VERSION 5.7 ;
  NOWIREEXTENSIONATPIN ON ;
  DIVIDERCHAR "/" ;
  BUSBITCHARS "[]" ;
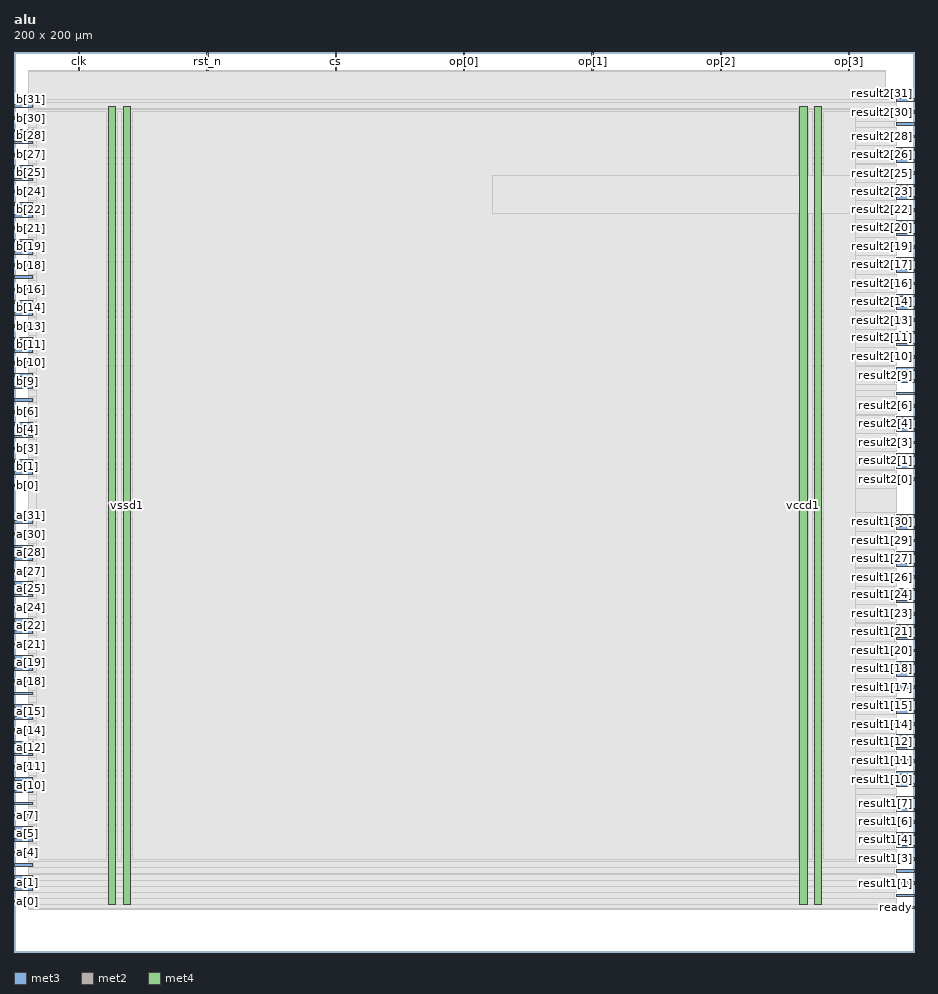
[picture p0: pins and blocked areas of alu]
MACRO alu
  CLASS BLOCK ;
  FOREIGN alu ;
  ORIGIN 0.000 0.000 ;
  SIZE 200.000 BY 200.000 ;
  PIN a[0]
    DIRECTION INPUT ;
    USE SIGNAL ;
    ANTENNAGATEAREA 0.593700 ;
    ANTENNADIFFAREA 0.434700 ;
    PORT
      LAYER met3 ;
        RECT 0.000 10.920 4.000 11.520 ;
    END
  END a[0]
  PIN a[10]
    DIRECTION INPUT ;
    USE SIGNAL ;
    ANTENNAGATEAREA 0.593700 ;
    ANTENNADIFFAREA 0.434700 ;
    PORT
      LAYER met3 ;
        RECT 0.000 38.120 4.000 38.720 ;
    END
  END a[10]
  PIN a[11]
    DIRECTION INPUT ;
    USE SIGNAL ;
    ANTENNAGATEAREA 0.647700 ;
    ANTENNADIFFAREA 0.434700 ;
    PORT
      LAYER met3 ;
        RECT 0.000 40.840 4.000 41.440 ;
    END
  END a[11]
  PIN a[12]
    DIRECTION INPUT ;
    USE SIGNAL ;
    ANTENNAGATEAREA 0.593700 ;
    ANTENNADIFFAREA 0.434700 ;
    PORT
      LAYER met3 ;
        RECT 0.000 43.560 4.000 44.160 ;
    END
  END a[12]
  PIN a[13]
    DIRECTION INPUT ;
    USE SIGNAL ;
    ANTENNAGATEAREA 0.593700 ;
    ANTENNADIFFAREA 0.434700 ;
    PORT
      LAYER met3 ;
        RECT 0.000 46.280 4.000 46.880 ;
    END
  END a[13]
  PIN a[14]
    DIRECTION INPUT ;
    USE SIGNAL ;
    ANTENNAGATEAREA 0.593700 ;
    ANTENNADIFFAREA 0.434700 ;
    PORT
      LAYER met3 ;
        RECT 0.000 49.000 4.000 49.600 ;
    END
  END a[14]
  PIN a[15]
    DIRECTION INPUT ;
    USE SIGNAL ;
    ANTENNAGATEAREA 0.593700 ;
    ANTENNADIFFAREA 0.434700 ;
    PORT
      LAYER met3 ;
        RECT 0.000 51.720 4.000 52.320 ;
    END
  END a[15]
  PIN a[16]
    DIRECTION INPUT ;
    USE SIGNAL ;
    ANTENNAGATEAREA 0.593700 ;
    ANTENNADIFFAREA 0.434700 ;
    PORT
      LAYER met3 ;
        RECT 0.000 54.440 4.000 55.040 ;
    END
  END a[16]
  PIN a[17]
    DIRECTION INPUT ;
    USE SIGNAL ;
    ANTENNAGATEAREA 0.647700 ;
    ANTENNADIFFAREA 0.434700 ;
    PORT
      LAYER met3 ;
        RECT 0.000 57.160 4.000 57.760 ;
    END
  END a[17]
  PIN a[18]
    DIRECTION INPUT ;
    USE SIGNAL ;
    ANTENNAGATEAREA 0.593700 ;
    ANTENNADIFFAREA 0.434700 ;
    PORT
      LAYER met3 ;
        RECT 0.000 59.880 4.000 60.480 ;
    END
  END a[18]
  PIN a[19]
    DIRECTION INPUT ;
    USE SIGNAL ;
    ANTENNAGATEAREA 0.593700 ;
    ANTENNADIFFAREA 0.434700 ;
    PORT
      LAYER met3 ;
        RECT 0.000 62.600 4.000 63.200 ;
    END
  END a[19]
  PIN a[1]
    DIRECTION INPUT ;
    USE SIGNAL ;
    ANTENNAGATEAREA 0.647700 ;
    ANTENNADIFFAREA 0.434700 ;
    PORT
      LAYER met3 ;
        RECT 0.000 13.640 4.000 14.240 ;
    END
  END a[1]
  PIN a[20]
    DIRECTION INPUT ;
    USE SIGNAL ;
    ANTENNAGATEAREA 0.647700 ;
    ANTENNADIFFAREA 0.434700 ;
    PORT
      LAYER met3 ;
        RECT 0.000 65.320 4.000 65.920 ;
    END
  END a[20]
  PIN a[21]
    DIRECTION INPUT ;
    USE SIGNAL ;
    ANTENNAGATEAREA 0.593700 ;
    ANTENNADIFFAREA 0.434700 ;
    PORT
      LAYER met3 ;
        RECT 0.000 68.040 4.000 68.640 ;
    END
  END a[21]
  PIN a[22]
    DIRECTION INPUT ;
    USE SIGNAL ;
    ANTENNAGATEAREA 0.593700 ;
    ANTENNADIFFAREA 0.434700 ;
    PORT
      LAYER met3 ;
        RECT 0.000 70.760 4.000 71.360 ;
    END
  END a[22]
  PIN a[23]
    DIRECTION INPUT ;
    USE SIGNAL ;
    ANTENNAGATEAREA 0.593700 ;
    ANTENNADIFFAREA 0.434700 ;
    PORT
      LAYER met3 ;
        RECT 0.000 73.480 4.000 74.080 ;
    END
  END a[23]
  PIN a[24]
    DIRECTION INPUT ;
    USE SIGNAL ;
    ANTENNAGATEAREA 0.593700 ;
    ANTENNADIFFAREA 0.434700 ;
    PORT
      LAYER met3 ;
        RECT 0.000 76.200 4.000 76.800 ;
    END
  END a[24]
  PIN a[25]
    DIRECTION INPUT ;
    USE SIGNAL ;
    ANTENNAGATEAREA 0.593700 ;
    ANTENNADIFFAREA 0.434700 ;
    PORT
      LAYER met3 ;
        RECT 0.000 78.920 4.000 79.520 ;
    END
  END a[25]
  PIN a[26]
    DIRECTION INPUT ;
    USE SIGNAL ;
    ANTENNAGATEAREA 0.593700 ;
    ANTENNADIFFAREA 0.434700 ;
    PORT
      LAYER met3 ;
        RECT 0.000 81.640 4.000 82.240 ;
    END
  END a[26]
  PIN a[27]
    DIRECTION INPUT ;
    USE SIGNAL ;
    ANTENNAGATEAREA 0.647700 ;
    ANTENNADIFFAREA 0.434700 ;
    PORT
      LAYER met3 ;
        RECT 0.000 84.360 4.000 84.960 ;
    END
  END a[27]
  PIN a[28]
    DIRECTION INPUT ;
    USE SIGNAL ;
    ANTENNAGATEAREA 0.593700 ;
    ANTENNADIFFAREA 0.434700 ;
    PORT
      LAYER met3 ;
        RECT 0.000 87.080 4.000 87.680 ;
    END
  END a[28]
  PIN a[29]
    DIRECTION INPUT ;
    USE SIGNAL ;
    ANTENNAGATEAREA 0.647700 ;
    ANTENNADIFFAREA 0.434700 ;
    PORT
      LAYER met3 ;
        RECT 0.000 89.800 4.000 90.400 ;
    END
  END a[29]
  PIN a[2]
    DIRECTION INPUT ;
    USE SIGNAL ;
    ANTENNAGATEAREA 0.647700 ;
    ANTENNADIFFAREA 0.434700 ;
    PORT
      LAYER met3 ;
        RECT 0.000 16.360 4.000 16.960 ;
    END
  END a[2]
  PIN a[30]
    DIRECTION INPUT ;
    USE SIGNAL ;
    ANTENNAGATEAREA 0.593700 ;
    ANTENNADIFFAREA 0.434700 ;
    PORT
      LAYER met3 ;
        RECT 0.000 92.520 4.000 93.120 ;
    END
  END a[30]
  PIN a[31]
    DIRECTION INPUT ;
    USE SIGNAL ;
    ANTENNAGATEAREA 0.647700 ;
    ANTENNADIFFAREA 0.434700 ;
    PORT
      LAYER met3 ;
        RECT 0.000 95.240 4.000 95.840 ;
    END
  END a[31]
  PIN a[3]
    DIRECTION INPUT ;
    USE SIGNAL ;
    ANTENNAGATEAREA 0.647700 ;
    ANTENNADIFFAREA 0.434700 ;
    PORT
      LAYER met3 ;
        RECT 0.000 19.080 4.000 19.680 ;
    END
  END a[3]
  PIN a[4]
    DIRECTION INPUT ;
    USE SIGNAL ;
    ANTENNAGATEAREA 0.647700 ;
    ANTENNADIFFAREA 0.434700 ;
    PORT
      LAYER met3 ;
        RECT 0.000 21.800 4.000 22.400 ;
    END
  END a[4]
  PIN a[5]
    DIRECTION INPUT ;
    USE SIGNAL ;
    ANTENNAGATEAREA 0.647700 ;
    ANTENNADIFFAREA 0.434700 ;
    PORT
      LAYER met3 ;
        RECT 0.000 24.520 4.000 25.120 ;
    END
  END a[5]
  PIN a[6]
    DIRECTION INPUT ;
    USE SIGNAL ;
    ANTENNAGATEAREA 0.647700 ;
    ANTENNADIFFAREA 0.434700 ;
    PORT
      LAYER met3 ;
        RECT 0.000 27.240 4.000 27.840 ;
    END
  END a[6]
  PIN a[7]
    DIRECTION INPUT ;
    USE SIGNAL ;
    ANTENNAGATEAREA 0.647700 ;
    ANTENNADIFFAREA 0.434700 ;
    PORT
      LAYER met3 ;
        RECT 0.000 29.960 4.000 30.560 ;
    END
  END a[7]
  PIN a[8]
    DIRECTION INPUT ;
    USE SIGNAL ;
    ANTENNAGATEAREA 0.647700 ;
    ANTENNADIFFAREA 0.434700 ;
    PORT
      LAYER met3 ;
        RECT 0.000 32.680 4.000 33.280 ;
    END
  END a[8]
  PIN a[9]
    DIRECTION INPUT ;
    USE SIGNAL ;
    ANTENNAGATEAREA 0.647700 ;
    ANTENNADIFFAREA 0.434700 ;
    PORT
      LAYER met3 ;
        RECT 0.000 35.400 4.000 36.000 ;
    END
  END a[9]
  PIN b[0]
    DIRECTION INPUT ;
    USE SIGNAL ;
    ANTENNAGATEAREA 0.647700 ;
    ANTENNADIFFAREA 0.434700 ;
    PORT
      LAYER met3 ;
        RECT 0.000 103.400 4.000 104.000 ;
    END
  END b[0]
  PIN b[10]
    DIRECTION INPUT ;
    USE SIGNAL ;
    ANTENNAGATEAREA 0.593700 ;
    ANTENNADIFFAREA 0.434700 ;
    PORT
      LAYER met3 ;
        RECT 0.000 130.600 4.000 131.200 ;
    END
  END b[10]
  PIN b[11]
    DIRECTION INPUT ;
    USE SIGNAL ;
    ANTENNAGATEAREA 0.593700 ;
    ANTENNADIFFAREA 0.434700 ;
    PORT
      LAYER met3 ;
        RECT 0.000 133.320 4.000 133.920 ;
    END
  END b[11]
  PIN b[12]
    DIRECTION INPUT ;
    USE SIGNAL ;
    ANTENNAGATEAREA 0.593700 ;
    ANTENNADIFFAREA 0.434700 ;
    PORT
      LAYER met3 ;
        RECT 0.000 136.040 4.000 136.640 ;
    END
  END b[12]
  PIN b[13]
    DIRECTION INPUT ;
    USE SIGNAL ;
    ANTENNAGATEAREA 0.593700 ;
    ANTENNADIFFAREA 0.434700 ;
    PORT
      LAYER met3 ;
        RECT 0.000 138.760 4.000 139.360 ;
    END
  END b[13]
  PIN b[14]
    DIRECTION INPUT ;
    USE SIGNAL ;
    ANTENNAGATEAREA 0.593700 ;
    ANTENNADIFFAREA 0.434700 ;
    PORT
      LAYER met3 ;
        RECT 0.000 141.480 4.000 142.080 ;
    END
  END b[14]
  PIN b[15]
    DIRECTION INPUT ;
    USE SIGNAL ;
    ANTENNAGATEAREA 0.647700 ;
    ANTENNADIFFAREA 0.434700 ;
    PORT
      LAYER met3 ;
        RECT 0.000 144.200 4.000 144.800 ;
    END
  END b[15]
  PIN b[16]
    DIRECTION INPUT ;
    USE SIGNAL ;
    ANTENNAGATEAREA 0.593700 ;
    ANTENNADIFFAREA 0.434700 ;
    PORT
      LAYER met3 ;
        RECT 0.000 146.920 4.000 147.520 ;
    END
  END b[16]
  PIN b[17]
    DIRECTION INPUT ;
    USE SIGNAL ;
    ANTENNAGATEAREA 0.593700 ;
    ANTENNADIFFAREA 0.434700 ;
    PORT
      LAYER met3 ;
        RECT 0.000 149.640 4.000 150.240 ;
    END
  END b[17]
  PIN b[18]
    DIRECTION INPUT ;
    USE SIGNAL ;
    ANTENNAGATEAREA 0.593700 ;
    ANTENNADIFFAREA 0.434700 ;
    PORT
      LAYER met3 ;
        RECT 0.000 152.360 4.000 152.960 ;
    END
  END b[18]
  PIN b[19]
    DIRECTION INPUT ;
    USE SIGNAL ;
    ANTENNAGATEAREA 0.593700 ;
    ANTENNADIFFAREA 0.434700 ;
    PORT
      LAYER met3 ;
        RECT 0.000 155.080 4.000 155.680 ;
    END
  END b[19]
  PIN b[1]
    DIRECTION INPUT ;
    USE SIGNAL ;
    ANTENNAGATEAREA 0.631200 ;
    ANTENNADIFFAREA 0.434700 ;
    PORT
      LAYER met3 ;
        RECT 0.000 106.120 4.000 106.720 ;
    END
  END b[1]
  PIN b[20]
    DIRECTION INPUT ;
    USE SIGNAL ;
    ANTENNAGATEAREA 0.647700 ;
    ANTENNADIFFAREA 0.434700 ;
    PORT
      LAYER met3 ;
        RECT 0.000 157.800 4.000 158.400 ;
    END
  END b[20]
  PIN b[21]
    DIRECTION INPUT ;
    USE SIGNAL ;
    ANTENNAGATEAREA 0.647700 ;
    ANTENNADIFFAREA 0.434700 ;
    PORT
      LAYER met3 ;
        RECT 0.000 160.520 4.000 161.120 ;
    END
  END b[21]
  PIN b[22]
    DIRECTION INPUT ;
    USE SIGNAL ;
    ANTENNAGATEAREA 0.593700 ;
    ANTENNADIFFAREA 0.434700 ;
    PORT
      LAYER met3 ;
        RECT 0.000 163.240 4.000 163.840 ;
    END
  END b[22]
  PIN b[23]
    DIRECTION INPUT ;
    USE SIGNAL ;
    ANTENNAGATEAREA 0.593700 ;
    ANTENNADIFFAREA 0.434700 ;
    PORT
      LAYER met3 ;
        RECT 0.000 165.960 4.000 166.560 ;
    END
  END b[23]
  PIN b[24]
    DIRECTION INPUT ;
    USE SIGNAL ;
    ANTENNAGATEAREA 0.593700 ;
    ANTENNADIFFAREA 0.434700 ;
    PORT
      LAYER met3 ;
        RECT 0.000 168.680 4.000 169.280 ;
    END
  END b[24]
  PIN b[25]
    DIRECTION INPUT ;
    USE SIGNAL ;
    ANTENNAGATEAREA 0.593700 ;
    ANTENNADIFFAREA 0.434700 ;
    PORT
      LAYER met3 ;
        RECT 0.000 171.400 4.000 172.000 ;
    END
  END b[25]
  PIN b[26]
    DIRECTION INPUT ;
    USE SIGNAL ;
    ANTENNAGATEAREA 0.593700 ;
    ANTENNADIFFAREA 0.434700 ;
    PORT
      LAYER met3 ;
        RECT 0.000 174.120 4.000 174.720 ;
    END
  END b[26]
  PIN b[27]
    DIRECTION INPUT ;
    USE SIGNAL ;
    ANTENNAGATEAREA 0.647700 ;
    ANTENNADIFFAREA 0.434700 ;
    PORT
      LAYER met3 ;
        RECT 0.000 176.840 4.000 177.440 ;
    END
  END b[27]
  PIN b[28]
    DIRECTION INPUT ;
    USE SIGNAL ;
    ANTENNAGATEAREA 0.647700 ;
    ANTENNADIFFAREA 0.434700 ;
    PORT
      LAYER met3 ;
        RECT 0.000 179.560 4.000 180.160 ;
    END
  END b[28]
  PIN b[29]
    DIRECTION INPUT ;
    USE SIGNAL ;
    ANTENNAGATEAREA 0.647700 ;
    ANTENNADIFFAREA 0.434700 ;
    PORT
      LAYER met3 ;
        RECT 0.000 182.280 4.000 182.880 ;
    END
  END b[29]
  PIN b[2]
    DIRECTION INPUT ;
    USE SIGNAL ;
    ANTENNAGATEAREA 0.631200 ;
    ANTENNADIFFAREA 0.434700 ;
    PORT
      LAYER met3 ;
        RECT 0.000 108.840 4.000 109.440 ;
    END
  END b[2]
  PIN b[30]
    DIRECTION INPUT ;
    USE SIGNAL ;
    ANTENNAGATEAREA 0.647700 ;
    ANTENNADIFFAREA 0.434700 ;
    PORT
      LAYER met3 ;
        RECT 0.000 185.000 4.000 185.600 ;
    END
  END b[30]
  PIN b[31]
    DIRECTION INPUT ;
    USE SIGNAL ;
    ANTENNAGATEAREA 0.593700 ;
    ANTENNADIFFAREA 0.434700 ;
    PORT
      LAYER met3 ;
        RECT 0.000 187.720 4.000 188.320 ;
    END
  END b[31]
  PIN b[3]
    DIRECTION INPUT ;
    USE SIGNAL ;
    ANTENNAGATEAREA 0.631200 ;
    ANTENNADIFFAREA 0.434700 ;
    PORT
      LAYER met3 ;
        RECT 0.000 111.560 4.000 112.160 ;
    END
  END b[3]
  PIN b[4]
    DIRECTION INPUT ;
    USE SIGNAL ;
    ANTENNAGATEAREA 0.647700 ;
    ANTENNADIFFAREA 0.434700 ;
    PORT
      LAYER met3 ;
        RECT 0.000 114.280 4.000 114.880 ;
    END
  END b[4]
  PIN b[5]
    DIRECTION INPUT ;
    USE SIGNAL ;
    ANTENNAGATEAREA 0.647700 ;
    ANTENNADIFFAREA 0.434700 ;
    PORT
      LAYER met3 ;
        RECT 0.000 117.000 4.000 117.600 ;
    END
  END b[5]
  PIN b[6]
    DIRECTION INPUT ;
    USE SIGNAL ;
    ANTENNAGATEAREA 0.593700 ;
    ANTENNADIFFAREA 0.434700 ;
    PORT
      LAYER met3 ;
        RECT 0.000 119.720 4.000 120.320 ;
    END
  END b[6]
  PIN b[7]
    DIRECTION INPUT ;
    USE SIGNAL ;
    ANTENNAGATEAREA 0.593700 ;
    ANTENNADIFFAREA 0.434700 ;
    PORT
      LAYER met3 ;
        RECT 0.000 122.440 4.000 123.040 ;
    END
  END b[7]
  PIN b[8]
    DIRECTION INPUT ;
    USE SIGNAL ;
    ANTENNAGATEAREA 0.647700 ;
    ANTENNADIFFAREA 0.434700 ;
    PORT
      LAYER met3 ;
        RECT 0.000 125.160 4.000 125.760 ;
    END
  END b[8]
  PIN b[9]
    DIRECTION INPUT ;
    USE SIGNAL ;
    ANTENNAGATEAREA 0.647700 ;
    ANTENNADIFFAREA 0.434700 ;
    PORT
      LAYER met3 ;
        RECT 0.000 127.880 4.000 128.480 ;
    END
  END b[9]
  PIN clk
    DIRECTION INPUT ;
    USE SIGNAL ;
    ANTENNAGATEAREA 1.286700 ;
    ANTENNADIFFAREA 0.434700 ;
    PORT
      LAYER met2 ;
        RECT 14.350 196.000 14.630 200.000 ;
    END
  END clk
  PIN cs
    DIRECTION INPUT ;
    USE SIGNAL ;
    ANTENNAGATEAREA 0.647700 ;
    ANTENNADIFFAREA 0.434700 ;
    PORT
      LAYER met2 ;
        RECT 71.390 196.000 71.670 200.000 ;
    END
  END cs
  PIN op[0]
    DIRECTION INPUT ;
    USE SIGNAL ;
    ANTENNAGATEAREA 0.560700 ;
    ANTENNADIFFAREA 0.434700 ;
    PORT
      LAYER met2 ;
        RECT 99.910 196.000 100.190 200.000 ;
    END
  END op[0]
  PIN op[1]
    DIRECTION INPUT ;
    USE SIGNAL ;
    ANTENNAGATEAREA 0.647700 ;
    ANTENNADIFFAREA 0.434700 ;
    PORT
      LAYER met2 ;
        RECT 128.430 196.000 128.710 200.000 ;
    END
  END op[1]
  PIN op[2]
    DIRECTION INPUT ;
    USE SIGNAL ;
    ANTENNAGATEAREA 0.647700 ;
    ANTENNADIFFAREA 0.434700 ;
    PORT
      LAYER met2 ;
        RECT 156.950 196.000 157.230 200.000 ;
    END
  END op[2]
  PIN op[3]
    DIRECTION INPUT ;
    USE SIGNAL ;
    ANTENNAGATEAREA 0.593700 ;
    ANTENNADIFFAREA 0.434700 ;
    PORT
      LAYER met2 ;
        RECT 185.470 196.000 185.750 200.000 ;
    END
  END op[3]
  PIN ready
    DIRECTION OUTPUT ;
    USE SIGNAL ;
    ANTENNADIFFAREA 0.445500 ;
    PORT
      LAYER met3 ;
        RECT 196.000 9.560 200.000 10.160 ;
    END
  END ready
  PIN result1[0]
    DIRECTION OUTPUT ;
    USE SIGNAL ;
    ANTENNADIFFAREA 0.445500 ;
    PORT
      LAYER met3 ;
        RECT 196.000 12.280 200.000 12.880 ;
    END
  END result1[0]
  PIN result1[10]
    DIRECTION OUTPUT ;
    USE SIGNAL ;
    ANTENNADIFFAREA 0.445500 ;
    PORT
      LAYER met3 ;
        RECT 196.000 39.480 200.000 40.080 ;
    END
  END result1[10]
  PIN result1[11]
    DIRECTION OUTPUT ;
    USE SIGNAL ;
    ANTENNADIFFAREA 0.445500 ;
    PORT
      LAYER met3 ;
        RECT 196.000 42.200 200.000 42.800 ;
    END
  END result1[11]
  PIN result1[12]
    DIRECTION OUTPUT ;
    USE SIGNAL ;
    ANTENNADIFFAREA 0.445500 ;
    PORT
      LAYER met3 ;
        RECT 196.000 44.920 200.000 45.520 ;
    END
  END result1[12]
  PIN result1[13]
    DIRECTION OUTPUT ;
    USE SIGNAL ;
    ANTENNADIFFAREA 0.445500 ;
    PORT
      LAYER met3 ;
        RECT 196.000 47.640 200.000 48.240 ;
    END
  END result1[13]
  PIN result1[14]
    DIRECTION OUTPUT ;
    USE SIGNAL ;
    ANTENNADIFFAREA 0.445500 ;
    PORT
      LAYER met3 ;
        RECT 196.000 50.360 200.000 50.960 ;
    END
  END result1[14]
  PIN result1[15]
    DIRECTION OUTPUT ;
    USE SIGNAL ;
    ANTENNADIFFAREA 0.445500 ;
    PORT
      LAYER met3 ;
        RECT 196.000 53.080 200.000 53.680 ;
    END
  END result1[15]
  PIN result1[16]
    DIRECTION OUTPUT ;
    USE SIGNAL ;
    ANTENNADIFFAREA 0.445500 ;
    PORT
      LAYER met3 ;
        RECT 196.000 55.800 200.000 56.400 ;
    END
  END result1[16]
  PIN result1[17]
    DIRECTION OUTPUT ;
    USE SIGNAL ;
    ANTENNADIFFAREA 0.445500 ;
    PORT
      LAYER met3 ;
        RECT 196.000 58.520 200.000 59.120 ;
    END
  END result1[17]
  PIN result1[18]
    DIRECTION OUTPUT ;
    USE SIGNAL ;
    ANTENNADIFFAREA 0.445500 ;
    PORT
      LAYER met3 ;
        RECT 196.000 61.240 200.000 61.840 ;
    END
  END result1[18]
  PIN result1[19]
    DIRECTION OUTPUT ;
    USE SIGNAL ;
    ANTENNADIFFAREA 0.445500 ;
    PORT
      LAYER met3 ;
        RECT 196.000 63.960 200.000 64.560 ;
    END
  END result1[19]
  PIN result1[1]
    DIRECTION OUTPUT ;
    USE SIGNAL ;
    ANTENNADIFFAREA 0.445500 ;
    PORT
      LAYER met3 ;
        RECT 196.000 15.000 200.000 15.600 ;
    END
  END result1[1]
  PIN result1[20]
    DIRECTION OUTPUT ;
    USE SIGNAL ;
    ANTENNADIFFAREA 0.445500 ;
    PORT
      LAYER met3 ;
        RECT 196.000 66.680 200.000 67.280 ;
    END
  END result1[20]
  PIN result1[21]
    DIRECTION OUTPUT ;
    USE SIGNAL ;
    ANTENNADIFFAREA 0.445500 ;
    PORT
      LAYER met3 ;
        RECT 196.000 69.400 200.000 70.000 ;
    END
  END result1[21]
  PIN result1[22]
    DIRECTION OUTPUT ;
    USE SIGNAL ;
    ANTENNADIFFAREA 0.445500 ;
    PORT
      LAYER met3 ;
        RECT 196.000 72.120 200.000 72.720 ;
    END
  END result1[22]
  PIN result1[23]
    DIRECTION OUTPUT ;
    USE SIGNAL ;
    ANTENNADIFFAREA 0.445500 ;
    PORT
      LAYER met3 ;
        RECT 196.000 74.840 200.000 75.440 ;
    END
  END result1[23]
  PIN result1[24]
    DIRECTION OUTPUT ;
    USE SIGNAL ;
    ANTENNADIFFAREA 0.445500 ;
    PORT
      LAYER met3 ;
        RECT 196.000 77.560 200.000 78.160 ;
    END
  END result1[24]
  PIN result1[25]
    DIRECTION OUTPUT ;
    USE SIGNAL ;
    ANTENNADIFFAREA 0.445500 ;
    PORT
      LAYER met3 ;
        RECT 196.000 80.280 200.000 80.880 ;
    END
  END result1[25]
  PIN result1[26]
    DIRECTION OUTPUT ;
    USE SIGNAL ;
    ANTENNADIFFAREA 0.445500 ;
    PORT
      LAYER met3 ;
        RECT 196.000 83.000 200.000 83.600 ;
    END
  END result1[26]
  PIN result1[27]
    DIRECTION OUTPUT ;
    USE SIGNAL ;
    ANTENNADIFFAREA 0.445500 ;
    PORT
      LAYER met3 ;
        RECT 196.000 85.720 200.000 86.320 ;
    END
  END result1[27]
  PIN result1[28]
    DIRECTION OUTPUT ;
    USE SIGNAL ;
    ANTENNADIFFAREA 0.445500 ;
    PORT
      LAYER met3 ;
        RECT 196.000 88.440 200.000 89.040 ;
    END
  END result1[28]
  PIN result1[29]
    DIRECTION OUTPUT ;
    USE SIGNAL ;
    ANTENNADIFFAREA 0.445500 ;
    PORT
      LAYER met3 ;
        RECT 196.000 91.160 200.000 91.760 ;
    END
  END result1[29]
  PIN result1[2]
    DIRECTION OUTPUT ;
    USE SIGNAL ;
    ANTENNADIFFAREA 0.445500 ;
    PORT
      LAYER met3 ;
        RECT 196.000 17.720 200.000 18.320 ;
    END
  END result1[2]
  PIN result1[30]
    DIRECTION OUTPUT ;
    USE SIGNAL ;
    ANTENNADIFFAREA 0.445500 ;
    PORT
      LAYER met3 ;
        RECT 196.000 93.880 200.000 94.480 ;
    END
  END result1[30]
  PIN result1[31]
    DIRECTION OUTPUT ;
    USE SIGNAL ;
    ANTENNADIFFAREA 0.445500 ;
    PORT
      LAYER met3 ;
        RECT 196.000 96.600 200.000 97.200 ;
    END
  END result1[31]
  PIN result1[3]
    DIRECTION OUTPUT ;
    USE SIGNAL ;
    ANTENNADIFFAREA 0.445500 ;
    PORT
      LAYER met3 ;
        RECT 196.000 20.440 200.000 21.040 ;
    END
  END result1[3]
  PIN result1[4]
    DIRECTION OUTPUT ;
    USE SIGNAL ;
    ANTENNADIFFAREA 0.445500 ;
    PORT
      LAYER met3 ;
        RECT 196.000 23.160 200.000 23.760 ;
    END
  END result1[4]
  PIN result1[5]
    DIRECTION OUTPUT ;
    USE SIGNAL ;
    ANTENNADIFFAREA 0.445500 ;
    PORT
      LAYER met3 ;
        RECT 196.000 25.880 200.000 26.480 ;
    END
  END result1[5]
  PIN result1[6]
    DIRECTION OUTPUT ;
    USE SIGNAL ;
    ANTENNADIFFAREA 0.445500 ;
    PORT
      LAYER met3 ;
        RECT 196.000 28.600 200.000 29.200 ;
    END
  END result1[6]
  PIN result1[7]
    DIRECTION OUTPUT ;
    USE SIGNAL ;
    ANTENNADIFFAREA 0.445500 ;
    PORT
      LAYER met3 ;
        RECT 196.000 31.320 200.000 31.920 ;
    END
  END result1[7]
  PIN result1[8]
    DIRECTION OUTPUT ;
    USE SIGNAL ;
    ANTENNADIFFAREA 0.445500 ;
    PORT
      LAYER met3 ;
        RECT 196.000 34.040 200.000 34.640 ;
    END
  END result1[8]
  PIN result1[9]
    DIRECTION OUTPUT ;
    USE SIGNAL ;
    ANTENNADIFFAREA 0.445500 ;
    PORT
      LAYER met3 ;
        RECT 196.000 36.760 200.000 37.360 ;
    END
  END result1[9]
  PIN result2[0]
    DIRECTION OUTPUT ;
    USE SIGNAL ;
    ANTENNADIFFAREA 0.445500 ;
    PORT
      LAYER met3 ;
        RECT 196.000 104.760 200.000 105.360 ;
    END
  END result2[0]
  PIN result2[10]
    DIRECTION OUTPUT ;
    USE SIGNAL ;
    ANTENNADIFFAREA 0.445500 ;
    PORT
      LAYER met3 ;
        RECT 196.000 131.960 200.000 132.560 ;
    END
  END result2[10]
  PIN result2[11]
    DIRECTION OUTPUT ;
    USE SIGNAL ;
    ANTENNADIFFAREA 0.445500 ;
    PORT
      LAYER met3 ;
        RECT 196.000 134.680 200.000 135.280 ;
    END
  END result2[11]
  PIN result2[12]
    DIRECTION OUTPUT ;
    USE SIGNAL ;
    ANTENNADIFFAREA 0.445500 ;
    PORT
      LAYER met3 ;
        RECT 196.000 137.400 200.000 138.000 ;
    END
  END result2[12]
  PIN result2[13]
    DIRECTION OUTPUT ;
    USE SIGNAL ;
    ANTENNADIFFAREA 0.445500 ;
    PORT
      LAYER met3 ;
        RECT 196.000 140.120 200.000 140.720 ;
    END
  END result2[13]
  PIN result2[14]
    DIRECTION OUTPUT ;
    USE SIGNAL ;
    ANTENNADIFFAREA 0.445500 ;
    PORT
      LAYER met3 ;
        RECT 196.000 142.840 200.000 143.440 ;
    END
  END result2[14]
  PIN result2[15]
    DIRECTION OUTPUT ;
    USE SIGNAL ;
    ANTENNADIFFAREA 0.445500 ;
    PORT
      LAYER met3 ;
        RECT 196.000 145.560 200.000 146.160 ;
    END
  END result2[15]
  PIN result2[16]
    DIRECTION OUTPUT ;
    USE SIGNAL ;
    ANTENNADIFFAREA 0.445500 ;
    PORT
      LAYER met3 ;
        RECT 196.000 148.280 200.000 148.880 ;
    END
  END result2[16]
  PIN result2[17]
    DIRECTION OUTPUT ;
    USE SIGNAL ;
    ANTENNADIFFAREA 0.445500 ;
    PORT
      LAYER met3 ;
        RECT 196.000 151.000 200.000 151.600 ;
    END
  END result2[17]
  PIN result2[18]
    DIRECTION OUTPUT ;
    USE SIGNAL ;
    ANTENNADIFFAREA 0.445500 ;
    PORT
      LAYER met3 ;
        RECT 196.000 153.720 200.000 154.320 ;
    END
  END result2[18]
  PIN result2[19]
    DIRECTION OUTPUT ;
    USE SIGNAL ;
    ANTENNADIFFAREA 0.445500 ;
    PORT
      LAYER met3 ;
        RECT 196.000 156.440 200.000 157.040 ;
    END
  END result2[19]
  PIN result2[1]
    DIRECTION OUTPUT ;
    USE SIGNAL ;
    ANTENNADIFFAREA 0.445500 ;
    PORT
      LAYER met3 ;
        RECT 196.000 107.480 200.000 108.080 ;
    END
  END result2[1]
  PIN result2[20]
    DIRECTION OUTPUT ;
    USE SIGNAL ;
    ANTENNADIFFAREA 0.445500 ;
    PORT
      LAYER met3 ;
        RECT 196.000 159.160 200.000 159.760 ;
    END
  END result2[20]
  PIN result2[21]
    DIRECTION OUTPUT ;
    USE SIGNAL ;
    ANTENNADIFFAREA 0.445500 ;
    PORT
      LAYER met3 ;
        RECT 196.000 161.880 200.000 162.480 ;
    END
  END result2[21]
  PIN result2[22]
    DIRECTION OUTPUT ;
    USE SIGNAL ;
    ANTENNADIFFAREA 0.445500 ;
    PORT
      LAYER met3 ;
        RECT 196.000 164.600 200.000 165.200 ;
    END
  END result2[22]
  PIN result2[23]
    DIRECTION OUTPUT ;
    USE SIGNAL ;
    ANTENNADIFFAREA 0.445500 ;
    PORT
      LAYER met3 ;
        RECT 196.000 167.320 200.000 167.920 ;
    END
  END result2[23]
  PIN result2[24]
    DIRECTION OUTPUT ;
    USE SIGNAL ;
    ANTENNADIFFAREA 0.445500 ;
    PORT
      LAYER met3 ;
        RECT 196.000 170.040 200.000 170.640 ;
    END
  END result2[24]
  PIN result2[25]
    DIRECTION OUTPUT ;
    USE SIGNAL ;
    ANTENNADIFFAREA 0.445500 ;
    PORT
      LAYER met3 ;
        RECT 196.000 172.760 200.000 173.360 ;
    END
  END result2[25]
  PIN result2[26]
    DIRECTION OUTPUT ;
    USE SIGNAL ;
    ANTENNADIFFAREA 0.445500 ;
    PORT
      LAYER met3 ;
        RECT 196.000 175.480 200.000 176.080 ;
    END
  END result2[26]
  PIN result2[27]
    DIRECTION OUTPUT ;
    USE SIGNAL ;
    ANTENNADIFFAREA 0.445500 ;
    PORT
      LAYER met3 ;
        RECT 196.000 178.200 200.000 178.800 ;
    END
  END result2[27]
  PIN result2[28]
    DIRECTION OUTPUT ;
    USE SIGNAL ;
    ANTENNADIFFAREA 0.445500 ;
    PORT
      LAYER met3 ;
        RECT 196.000 180.920 200.000 181.520 ;
    END
  END result2[28]
  PIN result2[29]
    DIRECTION OUTPUT ;
    USE SIGNAL ;
    ANTENNADIFFAREA 0.445500 ;
    PORT
      LAYER met3 ;
        RECT 196.000 183.640 200.000 184.240 ;
    END
  END result2[29]
  PIN result2[2]
    DIRECTION OUTPUT ;
    USE SIGNAL ;
    ANTENNADIFFAREA 0.445500 ;
    PORT
      LAYER met3 ;
        RECT 196.000 110.200 200.000 110.800 ;
    END
  END result2[2]
  PIN result2[30]
    DIRECTION OUTPUT ;
    USE SIGNAL ;
    ANTENNADIFFAREA 0.445500 ;
    PORT
      LAYER met3 ;
        RECT 196.000 186.360 200.000 186.960 ;
    END
  END result2[30]
  PIN result2[31]
    DIRECTION OUTPUT ;
    USE SIGNAL ;
    ANTENNADIFFAREA 0.445500 ;
    PORT
      LAYER met3 ;
        RECT 196.000 189.080 200.000 189.680 ;
    END
  END result2[31]
  PIN result2[3]
    DIRECTION OUTPUT ;
    USE SIGNAL ;
    ANTENNADIFFAREA 0.445500 ;
    PORT
      LAYER met3 ;
        RECT 196.000 112.920 200.000 113.520 ;
    END
  END result2[3]
  PIN result2[4]
    DIRECTION OUTPUT ;
    USE SIGNAL ;
    ANTENNADIFFAREA 0.445500 ;
    PORT
      LAYER met3 ;
        RECT 196.000 115.640 200.000 116.240 ;
    END
  END result2[4]
  PIN result2[5]
    DIRECTION OUTPUT ;
    USE SIGNAL ;
    ANTENNADIFFAREA 0.445500 ;
    PORT
      LAYER met3 ;
        RECT 196.000 118.360 200.000 118.960 ;
    END
  END result2[5]
  PIN result2[6]
    DIRECTION OUTPUT ;
    USE SIGNAL ;
    ANTENNADIFFAREA 0.445500 ;
    PORT
      LAYER met3 ;
        RECT 196.000 121.080 200.000 121.680 ;
    END
  END result2[6]
  PIN result2[7]
    DIRECTION OUTPUT ;
    USE SIGNAL ;
    ANTENNADIFFAREA 0.445500 ;
    PORT
      LAYER met3 ;
        RECT 196.000 123.800 200.000 124.400 ;
    END
  END result2[7]
  PIN result2[8]
    DIRECTION OUTPUT ;
    USE SIGNAL ;
    ANTENNADIFFAREA 0.445500 ;
    PORT
      LAYER met3 ;
        RECT 196.000 126.520 200.000 127.120 ;
    END
  END result2[8]
  PIN result2[9]
    DIRECTION OUTPUT ;
    USE SIGNAL ;
    ANTENNADIFFAREA 0.445500 ;
    PORT
      LAYER met3 ;
        RECT 196.000 129.240 200.000 129.840 ;
    END
  END result2[9]
  PIN rst_n
    DIRECTION INPUT ;
    USE SIGNAL ;
    ANTENNAGATEAREA 0.647700 ;
    ANTENNADIFFAREA 0.434700 ;
    PORT
      LAYER met2 ;
        RECT 42.870 196.000 43.150 200.000 ;
    END
  END rst_n
  PIN vccd1
    DIRECTION INOUT ;
    USE POWER ;
    PORT
      LAYER met4 ;
        RECT 21.040 10.640 22.640 187.920 ;
    END
    PORT
      LAYER met4 ;
        RECT 174.640 10.640 176.240 187.920 ;
    END
  END vccd1
  PIN vssd1
    DIRECTION INOUT ;
    USE GROUND ;
    PORT
      LAYER met4 ;
        RECT 24.340 10.640 25.940 187.920 ;
    END
    PORT
      LAYER met4 ;
        RECT 177.940 10.640 179.540 187.920 ;
    END
  END vssd1
  OBS
      LAYER nwell ;
        RECT 5.330 10.795 194.310 187.870 ;
      LAYER li1 ;
        RECT 5.520 10.795 194.120 187.765 ;
      LAYER met1 ;
        RECT 3.290 9.560 194.120 190.020 ;
      LAYER met2 ;
        RECT 3.310 195.720 14.070 196.000 ;
        RECT 14.910 195.720 42.590 196.000 ;
        RECT 43.430 195.720 71.110 196.000 ;
        RECT 71.950 195.720 99.630 196.000 ;
        RECT 100.470 195.720 128.150 196.000 ;
        RECT 128.990 195.720 156.670 196.000 ;
        RECT 157.510 195.720 185.190 196.000 ;
        RECT 186.030 195.720 193.570 196.000 ;
        RECT 3.310 9.530 193.570 195.720 ;
      LAYER met3 ;
        RECT 3.285 188.720 195.600 189.545 ;
        RECT 4.400 188.680 195.600 188.720 ;
        RECT 4.400 187.360 196.000 188.680 ;
        RECT 4.400 187.320 195.600 187.360 ;
        RECT 3.285 186.000 195.600 187.320 ;
        RECT 4.400 185.960 195.600 186.000 ;
        RECT 4.400 184.640 196.000 185.960 ;
        RECT 4.400 184.600 195.600 184.640 ;
        RECT 3.285 183.280 195.600 184.600 ;
        RECT 4.400 183.240 195.600 183.280 ;
        RECT 4.400 181.920 196.000 183.240 ;
        RECT 4.400 181.880 195.600 181.920 ;
        RECT 3.285 180.560 195.600 181.880 ;
        RECT 4.400 180.520 195.600 180.560 ;
        RECT 4.400 179.200 196.000 180.520 ;
        RECT 4.400 179.160 195.600 179.200 ;
        RECT 3.285 177.840 195.600 179.160 ;
        RECT 4.400 177.800 195.600 177.840 ;
        RECT 4.400 176.480 196.000 177.800 ;
        RECT 4.400 176.440 195.600 176.480 ;
        RECT 3.285 175.120 195.600 176.440 ;
        RECT 4.400 175.080 195.600 175.120 ;
        RECT 4.400 173.760 196.000 175.080 ;
        RECT 4.400 173.720 195.600 173.760 ;
        RECT 3.285 172.400 195.600 173.720 ;
        RECT 4.400 172.360 195.600 172.400 ;
        RECT 4.400 171.040 196.000 172.360 ;
        RECT 4.400 171.000 195.600 171.040 ;
        RECT 3.285 169.680 195.600 171.000 ;
        RECT 4.400 169.640 195.600 169.680 ;
        RECT 4.400 168.320 196.000 169.640 ;
        RECT 4.400 168.280 195.600 168.320 ;
        RECT 3.285 166.960 195.600 168.280 ;
        RECT 4.400 166.920 195.600 166.960 ;
        RECT 4.400 165.600 196.000 166.920 ;
        RECT 4.400 165.560 195.600 165.600 ;
        RECT 3.285 164.240 195.600 165.560 ;
        RECT 4.400 164.200 195.600 164.240 ;
        RECT 4.400 162.880 196.000 164.200 ;
        RECT 4.400 162.840 195.600 162.880 ;
        RECT 3.285 161.520 195.600 162.840 ;
        RECT 4.400 161.480 195.600 161.520 ;
        RECT 4.400 160.160 196.000 161.480 ;
        RECT 4.400 160.120 195.600 160.160 ;
        RECT 3.285 158.800 195.600 160.120 ;
        RECT 4.400 158.760 195.600 158.800 ;
        RECT 4.400 157.440 196.000 158.760 ;
        RECT 4.400 157.400 195.600 157.440 ;
        RECT 3.285 156.080 195.600 157.400 ;
        RECT 4.400 156.040 195.600 156.080 ;
        RECT 4.400 154.720 196.000 156.040 ;
        RECT 4.400 154.680 195.600 154.720 ;
        RECT 3.285 153.360 195.600 154.680 ;
        RECT 4.400 153.320 195.600 153.360 ;
        RECT 4.400 152.000 196.000 153.320 ;
        RECT 4.400 151.960 195.600 152.000 ;
        RECT 3.285 150.640 195.600 151.960 ;
        RECT 4.400 150.600 195.600 150.640 ;
        RECT 4.400 149.280 196.000 150.600 ;
        RECT 4.400 149.240 195.600 149.280 ;
        RECT 3.285 147.920 195.600 149.240 ;
        RECT 4.400 147.880 195.600 147.920 ;
        RECT 4.400 146.560 196.000 147.880 ;
        RECT 4.400 146.520 195.600 146.560 ;
        RECT 3.285 145.200 195.600 146.520 ;
        RECT 4.400 145.160 195.600 145.200 ;
        RECT 4.400 143.840 196.000 145.160 ;
        RECT 4.400 143.800 195.600 143.840 ;
        RECT 3.285 142.480 195.600 143.800 ;
        RECT 4.400 142.440 195.600 142.480 ;
        RECT 4.400 141.120 196.000 142.440 ;
        RECT 4.400 141.080 195.600 141.120 ;
        RECT 3.285 139.760 195.600 141.080 ;
        RECT 4.400 139.720 195.600 139.760 ;
        RECT 4.400 138.400 196.000 139.720 ;
        RECT 4.400 138.360 195.600 138.400 ;
        RECT 3.285 137.040 195.600 138.360 ;
        RECT 4.400 137.000 195.600 137.040 ;
        RECT 4.400 135.680 196.000 137.000 ;
        RECT 4.400 135.640 195.600 135.680 ;
        RECT 3.285 134.320 195.600 135.640 ;
        RECT 4.400 134.280 195.600 134.320 ;
        RECT 4.400 132.960 196.000 134.280 ;
        RECT 4.400 132.920 195.600 132.960 ;
        RECT 3.285 131.600 195.600 132.920 ;
        RECT 4.400 131.560 195.600 131.600 ;
        RECT 4.400 130.240 196.000 131.560 ;
        RECT 4.400 130.200 195.600 130.240 ;
        RECT 3.285 128.880 195.600 130.200 ;
        RECT 4.400 128.840 195.600 128.880 ;
        RECT 4.400 127.520 196.000 128.840 ;
        RECT 4.400 127.480 195.600 127.520 ;
        RECT 3.285 126.160 195.600 127.480 ;
        RECT 4.400 126.120 195.600 126.160 ;
        RECT 4.400 124.800 196.000 126.120 ;
        RECT 4.400 124.760 195.600 124.800 ;
        RECT 3.285 123.440 195.600 124.760 ;
        RECT 4.400 123.400 195.600 123.440 ;
        RECT 4.400 122.080 196.000 123.400 ;
        RECT 4.400 122.040 195.600 122.080 ;
        RECT 3.285 120.720 195.600 122.040 ;
        RECT 4.400 120.680 195.600 120.720 ;
        RECT 4.400 119.360 196.000 120.680 ;
        RECT 4.400 119.320 195.600 119.360 ;
        RECT 3.285 118.000 195.600 119.320 ;
        RECT 4.400 117.960 195.600 118.000 ;
        RECT 4.400 116.640 196.000 117.960 ;
        RECT 4.400 116.600 195.600 116.640 ;
        RECT 3.285 115.280 195.600 116.600 ;
        RECT 4.400 115.240 195.600 115.280 ;
        RECT 4.400 113.920 196.000 115.240 ;
        RECT 4.400 113.880 195.600 113.920 ;
        RECT 3.285 112.560 195.600 113.880 ;
        RECT 4.400 112.520 195.600 112.560 ;
        RECT 4.400 111.200 196.000 112.520 ;
        RECT 4.400 111.160 195.600 111.200 ;
        RECT 3.285 109.840 195.600 111.160 ;
        RECT 4.400 109.800 195.600 109.840 ;
        RECT 4.400 108.480 196.000 109.800 ;
        RECT 4.400 108.440 195.600 108.480 ;
        RECT 3.285 107.120 195.600 108.440 ;
        RECT 4.400 107.080 195.600 107.120 ;
        RECT 4.400 105.760 196.000 107.080 ;
        RECT 4.400 105.720 195.600 105.760 ;
        RECT 3.285 104.400 195.600 105.720 ;
        RECT 4.400 104.360 195.600 104.400 ;
        RECT 4.400 103.000 196.000 104.360 ;
        RECT 3.285 97.600 196.000 103.000 ;
        RECT 3.285 96.240 195.600 97.600 ;
        RECT 4.400 96.200 195.600 96.240 ;
        RECT 4.400 94.880 196.000 96.200 ;
        RECT 4.400 94.840 195.600 94.880 ;
        RECT 3.285 93.520 195.600 94.840 ;
        RECT 4.400 93.480 195.600 93.520 ;
        RECT 4.400 92.160 196.000 93.480 ;
        RECT 4.400 92.120 195.600 92.160 ;
        RECT 3.285 90.800 195.600 92.120 ;
        RECT 4.400 90.760 195.600 90.800 ;
        RECT 4.400 89.440 196.000 90.760 ;
        RECT 4.400 89.400 195.600 89.440 ;
        RECT 3.285 88.080 195.600 89.400 ;
        RECT 4.400 88.040 195.600 88.080 ;
        RECT 4.400 86.720 196.000 88.040 ;
        RECT 4.400 86.680 195.600 86.720 ;
        RECT 3.285 85.360 195.600 86.680 ;
        RECT 4.400 85.320 195.600 85.360 ;
        RECT 4.400 84.000 196.000 85.320 ;
        RECT 4.400 83.960 195.600 84.000 ;
        RECT 3.285 82.640 195.600 83.960 ;
        RECT 4.400 82.600 195.600 82.640 ;
        RECT 4.400 81.280 196.000 82.600 ;
        RECT 4.400 81.240 195.600 81.280 ;
        RECT 3.285 79.920 195.600 81.240 ;
        RECT 4.400 79.880 195.600 79.920 ;
        RECT 4.400 78.560 196.000 79.880 ;
        RECT 4.400 78.520 195.600 78.560 ;
        RECT 3.285 77.200 195.600 78.520 ;
        RECT 4.400 77.160 195.600 77.200 ;
        RECT 4.400 75.840 196.000 77.160 ;
        RECT 4.400 75.800 195.600 75.840 ;
        RECT 3.285 74.480 195.600 75.800 ;
        RECT 4.400 74.440 195.600 74.480 ;
        RECT 4.400 73.120 196.000 74.440 ;
        RECT 4.400 73.080 195.600 73.120 ;
        RECT 3.285 71.760 195.600 73.080 ;
        RECT 4.400 71.720 195.600 71.760 ;
        RECT 4.400 70.400 196.000 71.720 ;
        RECT 4.400 70.360 195.600 70.400 ;
        RECT 3.285 69.040 195.600 70.360 ;
        RECT 4.400 69.000 195.600 69.040 ;
        RECT 4.400 67.680 196.000 69.000 ;
        RECT 4.400 67.640 195.600 67.680 ;
        RECT 3.285 66.320 195.600 67.640 ;
        RECT 4.400 66.280 195.600 66.320 ;
        RECT 4.400 64.960 196.000 66.280 ;
        RECT 4.400 64.920 195.600 64.960 ;
        RECT 3.285 63.600 195.600 64.920 ;
        RECT 4.400 63.560 195.600 63.600 ;
        RECT 4.400 62.240 196.000 63.560 ;
        RECT 4.400 62.200 195.600 62.240 ;
        RECT 3.285 60.880 195.600 62.200 ;
        RECT 4.400 60.840 195.600 60.880 ;
        RECT 4.400 59.520 196.000 60.840 ;
        RECT 4.400 59.480 195.600 59.520 ;
        RECT 3.285 58.160 195.600 59.480 ;
        RECT 4.400 58.120 195.600 58.160 ;
        RECT 4.400 56.800 196.000 58.120 ;
        RECT 4.400 56.760 195.600 56.800 ;
        RECT 3.285 55.440 195.600 56.760 ;
        RECT 4.400 55.400 195.600 55.440 ;
        RECT 4.400 54.080 196.000 55.400 ;
        RECT 4.400 54.040 195.600 54.080 ;
        RECT 3.285 52.720 195.600 54.040 ;
        RECT 4.400 52.680 195.600 52.720 ;
        RECT 4.400 51.360 196.000 52.680 ;
        RECT 4.400 51.320 195.600 51.360 ;
        RECT 3.285 50.000 195.600 51.320 ;
        RECT 4.400 49.960 195.600 50.000 ;
        RECT 4.400 48.640 196.000 49.960 ;
        RECT 4.400 48.600 195.600 48.640 ;
        RECT 3.285 47.280 195.600 48.600 ;
        RECT 4.400 47.240 195.600 47.280 ;
        RECT 4.400 45.920 196.000 47.240 ;
        RECT 4.400 45.880 195.600 45.920 ;
        RECT 3.285 44.560 195.600 45.880 ;
        RECT 4.400 44.520 195.600 44.560 ;
        RECT 4.400 43.200 196.000 44.520 ;
        RECT 4.400 43.160 195.600 43.200 ;
        RECT 3.285 41.840 195.600 43.160 ;
        RECT 4.400 41.800 195.600 41.840 ;
        RECT 4.400 40.480 196.000 41.800 ;
        RECT 4.400 40.440 195.600 40.480 ;
        RECT 3.285 39.120 195.600 40.440 ;
        RECT 4.400 39.080 195.600 39.120 ;
        RECT 4.400 37.760 196.000 39.080 ;
        RECT 4.400 37.720 195.600 37.760 ;
        RECT 3.285 36.400 195.600 37.720 ;
        RECT 4.400 36.360 195.600 36.400 ;
        RECT 4.400 35.040 196.000 36.360 ;
        RECT 4.400 35.000 195.600 35.040 ;
        RECT 3.285 33.680 195.600 35.000 ;
        RECT 4.400 33.640 195.600 33.680 ;
        RECT 4.400 32.320 196.000 33.640 ;
        RECT 4.400 32.280 195.600 32.320 ;
        RECT 3.285 30.960 195.600 32.280 ;
        RECT 4.400 30.920 195.600 30.960 ;
        RECT 4.400 29.600 196.000 30.920 ;
        RECT 4.400 29.560 195.600 29.600 ;
        RECT 3.285 28.240 195.600 29.560 ;
        RECT 4.400 28.200 195.600 28.240 ;
        RECT 4.400 26.880 196.000 28.200 ;
        RECT 4.400 26.840 195.600 26.880 ;
        RECT 3.285 25.520 195.600 26.840 ;
        RECT 4.400 25.480 195.600 25.520 ;
        RECT 4.400 24.160 196.000 25.480 ;
        RECT 4.400 24.120 195.600 24.160 ;
        RECT 3.285 22.800 195.600 24.120 ;
        RECT 4.400 22.760 195.600 22.800 ;
        RECT 4.400 21.440 196.000 22.760 ;
        RECT 4.400 21.400 195.600 21.440 ;
        RECT 3.285 20.080 195.600 21.400 ;
        RECT 4.400 20.040 195.600 20.080 ;
        RECT 4.400 18.720 196.000 20.040 ;
        RECT 4.400 18.680 195.600 18.720 ;
        RECT 3.285 17.360 195.600 18.680 ;
        RECT 4.400 17.320 195.600 17.360 ;
        RECT 4.400 16.000 196.000 17.320 ;
        RECT 4.400 15.960 195.600 16.000 ;
        RECT 3.285 14.640 195.600 15.960 ;
        RECT 4.400 14.600 195.600 14.640 ;
        RECT 4.400 13.280 196.000 14.600 ;
        RECT 4.400 13.240 195.600 13.280 ;
        RECT 3.285 11.920 195.600 13.240 ;
        RECT 4.400 11.880 195.600 11.920 ;
        RECT 4.400 10.560 196.000 11.880 ;
        RECT 4.400 10.520 195.600 10.560 ;
        RECT 3.285 9.695 195.600 10.520 ;
      LAYER met4 ;
        RECT 4.895 20.575 20.640 186.825 ;
        RECT 23.040 20.575 23.940 186.825 ;
        RECT 26.340 20.575 174.240 186.825 ;
        RECT 176.640 20.575 177.540 186.825 ;
        RECT 179.940 20.575 186.890 186.825 ;
      LAYER met5 ;
        RECT 106.380 164.100 187.100 172.500 ;
  END
END alu
END LIBRARY

